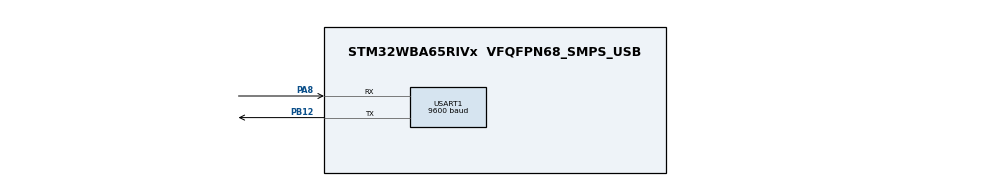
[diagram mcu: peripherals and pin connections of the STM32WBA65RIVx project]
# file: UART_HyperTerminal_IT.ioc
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CORTEX_M33_NS.userName=CORTEX_M33
Mcu.Family=STM32WBA
Mcu.Name=STM32WBA65RIVx
Mcu.Package=VFQFPN68_SMPS_USB
NVIC.PriorityGroup=NVIC_PRIORITYGROUP_4
NVIC.USART1_IRQn=true\:0\:0\:false\:false\:true\:true\:true\:true
OSC_IN.Mode=HSE-External-Oscillator
OSC_IN.Signal=RCC_OSC_IN
OSC_OUT.Mode=HSE-External-Oscillator
OSC_OUT.Signal=RCC_OSC_OUT
PA8.GPIO_PuPd=GPIO_PULLUP
PA8.Mode=Asynchronous
PA8.Signal=USART1_RX
PB12.GPIO_PuPd=GPIO_PULLUP
PB12.Mode=Asynchronous
PB12.Signal=USART1_TX
ProjectManager.HeapSize=0x200
ProjectManager.StackSize=0x400
ProjectManager.TargetToolchain=EWARM V9.20
RCC.ADCFreq_Value=100000000
RCC.AHB5CLKDivider=DIV4
RCC.AHBFreq_Value=100000000
RCC.APB1Freq_Value=100000000
RCC.APB1TimFreq_Value=100000000
RCC.APB2Freq_Value=100000000
RCC.APB2TimFreq_Value=100000000
RCC.CortexFreq_Value=12500000
RCC.HCLKFreq_Value=100000000
RCC.HSE_VALUE=32000000
RCC.HSI_VALUE=16000000
RCC.LSE_VALUE=32768
RCC.LSI1_VALUE=32000
RCC.LSI2_VALUE=32000
RCC.PLLFRACN=4096
RCC.PLLM=2
RCC.PLLN=12
RCC.PLLSourceVirtual=RCC_PLLSOURCE_HSE
RCC.SYSCLKFreq_VALUE=100000000
RCC.SYSCLKSourceVirtual=RCC_SYSCLKSOURCE_PLLCLK
RCC.VCOOutputFreq_Value=200000000
USART1.AutoBaudRateEnableParam=UART_ADVFEATURE_AUTOBAUDRATE_DISABLE
USART1.BaudRate=9600
USART1.DMADisableonRxErrorParam=ADVFEATURE_DMA_ENABLEONRXERROR
USART1.DataInvertParam=ADVFEATURE_DATAINV_DISABLE
USART1.MSBFirstParam=ADVFEATURE_MSBFIRST_DISABLE
USART1.Mode=MODE_TX_RX
USART1.OneBitSampling=UART_ONE_BIT_SAMPLE_DISABLE
USART1.OverSampling=UART_OVERSAMPLING_16
USART1.OverrunDisableParam=ADVFEATURE_OVERRUN_ENABLE
USART1.Parity=PARITY_ODD
USART1.RxPinLevelInvertParam=ADVFEATURE_RXINV_DISABLE
USART1.StopBits=STOPBITS_1
USART1.SwapParam=ADVFEATURE_SWAP_DISABLE
USART1.TxPinLevelInvertParam=ADVFEATURE_TXINV_DISABLE
USART1.VirtualMode-Asynchronous=VM_ASYNC
USART1.WordLength=WORDLENGTH_8B
VP_CORTEX_M33_NS_VS_Hclk.Mode=Hclk_Mode
VP_ICACHE_VS_ICACHE.Mode=DirectMappedCache
VP_PWR_VS_SECSignals.Mode=Security/Privilege
board=custom

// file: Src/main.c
/* USER CODE BEGIN Header */
/**
  ******************************************************************************
  * @file    UART/UART_HyperTerminal_IT/Src/main.c
  * @author  MCD Application Team
  * @brief   This sample code shows how to use UART HAL API to transmit
  *          and receive a data buffer with a communication process based on
  *          Interrupt transfer.
  *          The communication is done with the Hyperterminal PC application.
  ******************************************************************************
  * @attention
  *
  * Copyright (c) 2024 STMicroelectronics.
  * All rights reserved.
  *
  * This software is licensed under terms that can be found in the LICENSE file
  * in the root directory of this software component.
  * If no LICENSE file comes with this software, it is provided AS-IS.
  *
  ******************************************************************************
  */
/* USER CODE END Header */
#include "main.h"

UART_HandleTypeDef huart1;

/* USER CODE BEGIN PV */
/* Buffer used for transmission */
uint8_t aTxStartMessage[] = "\n\r ****UART-Hyperterminal communication based on IT ****\n\r Enter 10 characters using keyboard :\n\r";
uint8_t aTxEndMessage[] = "\n\r Example Finished\n\r";

/* Buffer used for reception */
uint8_t aRxBuffer[RXBUFFERSIZE];
/* USER CODE END PV */

void SystemClock_Config(void);
static void MX_GPIO_Init(void);
static void MX_USART1_UART_Init(void);
static void MX_ICACHE_Init(void);

int main(void)
{

  /* USER CODE BEGIN 1 */
  /* STM32WBAxx HAL library initialization:
       - Systick timer is configured by default as source of time base, but user
             can eventually implement his proper time base source (a general purpose
             timer for example or other time source), keeping in mind that Time base
             duration should be kept 1ms since PPP_TIMEOUT_VALUEs are defined and
             handled in milliseconds basis.
       - Set NVIC Group Priority to 4
       - Low Level Initialization
     */
  /* USER CODE END 1 */

  /* MCU Configuration--------------------------------------------------------*/

  /* Reset of all peripherals, Initializes the Flash interface and the Systick. */
  HAL_Init();

  /* Configure the system clock */
  SystemClock_Config();

  /* USER CODE BEGIN SysInit */
  /* Configure leds */
  /* Configure LD1 and LD3 */
  BSP_LED_Init(LD1);
  BSP_LED_Init(LD3);
  /* USER CODE END SysInit */

  /* Initialize all configured peripherals */
  MX_GPIO_Init();
  MX_USART1_UART_Init();
  MX_ICACHE_Init();
  /* USER CODE BEGIN 2 */

  /*##-1- Start the transmission process #####################################*/
  /* While the UART in reception process, user can transmit data through
     "aTxBuffer" buffer */
  if(HAL_UART_Transmit_IT(&huart1, (uint8_t*)aTxStartMessage, TXSTARTMESSAGESIZE)!= HAL_OK)
  {
    /* Transfer error in transmission process */
    Error_Handler();
  }

  /*##-2- Put UART peripheral in reception process ###########################*/
  /* Any data received will be stored in "aRxBuffer" buffer : the number max of
     data received is 10 */
  if(HAL_UART_Receive_IT(&huart1, (uint8_t *)aRxBuffer, RXBUFFERSIZE) != HAL_OK)
  {
    /* Transfer error in reception process */
    Error_Handler();
  }

  /*##-3- Wait for the end of the transfer ###################################*/
  /*  Before starting a new communication transfer, you need to check the current
      state of the peripheral; if it is busy you need to wait for the end of current
      transfer before starting a new one.
      For simplicity reasons, this example is just waiting till the end of the
      transfer, but application may perform other tasks while transfer operation
      is ongoing. */
  while (HAL_UART_GetState(&huart1) != HAL_UART_STATE_READY)
  {
  }

  /*##-4- Send the received Buffer ###########################################*/
  if(HAL_UART_Transmit_IT(&huart1, (uint8_t*)aRxBuffer, RXBUFFERSIZE)!= HAL_OK)
  {
    /* Transfer error in transmission process */
    Error_Handler();
  }

  /*##-5- Wait for the end of the transfer ###################################*/
  /*  Before starting a new communication transfer, you need to check the current
      state of the peripheral; if it is busy you need to wait for the end of current
      transfer before starting a new one.
      For simplicity reasons, this example is just waiting till the end of the
      transfer, but application may perform other tasks while transfer operation
      is ongoing. */
  while (HAL_UART_GetState(&huart1) != HAL_UART_STATE_READY)
  {
  }

  /*##-6- Send the End Message ###############################################*/
  if(HAL_UART_Transmit_IT(&huart1, (uint8_t*)aTxEndMessage, TXENDMESSAGESIZE)!= HAL_OK)
  {
    /* Transfer error in transmission process */
    Error_Handler();
  }

  /*##-7- Wait for the end of the transfer ###################################*/
  while (HAL_UART_GetState(&huart1) != HAL_UART_STATE_READY)
  {
  }

  /* Turn on LD1 if test passes then enter infinite loop */
  BSP_LED_On(LD1);

  /* USER CODE END 2 */

  /* Infinite loop */
  while (1)
  {

  }
}

void SystemClock_Config(void)
{
  RCC_OscInitTypeDef RCC_OscInitStruct = {0};
  RCC_ClkInitTypeDef RCC_ClkInitStruct = {0};

  /** Supply configuration update enable
  */
  HAL_PWREx_ConfigSupply(PWR_LDO_SUPPLY);

  /** Configure the main internal regulator output voltage
  */
  if (HAL_PWREx_ControlVoltageScaling(PWR_REGULATOR_VOLTAGE_SCALE1) != HAL_OK)
  {
    Error_Handler();
  }

  /** Initializes the CPU, AHB and APB busses clocks
  */
  RCC_OscInitStruct.OscillatorType = RCC_OSCILLATORTYPE_HSE;
  RCC_OscInitStruct.HSEState = RCC_HSE_ON;
  RCC_OscInitStruct.HSEDiv = RCC_HSE_DIV1;
  RCC_OscInitStruct.PLL1.PLLState = RCC_PLL_ON;
  RCC_OscInitStruct.PLL1.PLLSource = RCC_PLLSOURCE_HSE;
  RCC_OscInitStruct.PLL1.PLLM = 2;
  RCC_OscInitStruct.PLL1.PLLN = 12;
  RCC_OscInitStruct.PLL1.PLLP = 2;
  RCC_OscInitStruct.PLL1.PLLQ = 2;
  RCC_OscInitStruct.PLL1.PLLR = 2;
  RCC_OscInitStruct.PLL1.PLLFractional = 4096;
  if (HAL_RCC_OscConfig(&RCC_OscInitStruct) != HAL_OK)
  {
    Error_Handler();
  }

  /** Initializes the CPU, AHB and APB busses clocks
  */
  RCC_ClkInitStruct.ClockType = RCC_CLOCKTYPE_HCLK|RCC_CLOCKTYPE_SYSCLK
                              |RCC_CLOCKTYPE_PCLK1|RCC_CLOCKTYPE_PCLK2
                              |RCC_CLOCKTYPE_PCLK7|RCC_CLOCKTYPE_HCLK5;
  RCC_ClkInitStruct.SYSCLKSource = RCC_SYSCLKSOURCE_PLLCLK;
  RCC_ClkInitStruct.AHBCLKDivider = RCC_SYSCLK_DIV1;
  RCC_ClkInitStruct.APB1CLKDivider = RCC_HCLK_DIV1;
  RCC_ClkInitStruct.APB2CLKDivider = RCC_HCLK_DIV1;
  RCC_ClkInitStruct.APB7CLKDivider = RCC_HCLK_DIV1;
  RCC_ClkInitStruct.AHB5_PLL1_CLKDivider = RCC_SYSCLK_PLL1_DIV4;
  RCC_ClkInitStruct.AHB5_HSEHSI_CLKDivider = RCC_SYSCLK_HSEHSI_DIV1;

  if (HAL_RCC_ClockConfig(&RCC_ClkInitStruct, FLASH_LATENCY_3) != HAL_OK)
  {
    Error_Handler();
  }
}

static void MX_ICACHE_Init(void)
{

  /** Enable instruction cache in 1-way (direct mapped cache)
  */
  if (HAL_ICACHE_ConfigAssociativityMode(ICACHE_1WAY) != HAL_OK)
  {
    Error_Handler();
  }
  if (HAL_ICACHE_Enable() != HAL_OK)
  {
    Error_Handler();
  }

}

static void MX_USART1_UART_Init(void)
{

  huart1.Instance = USART1;
  huart1.Init.BaudRate = 9600;
  huart1.Init.WordLength = UART_WORDLENGTH_8B;
  huart1.Init.StopBits = UART_STOPBITS_1;
  huart1.Init.Parity = UART_PARITY_ODD;
  huart1.Init.Mode = UART_MODE_TX_RX;
  huart1.Init.HwFlowCtl = UART_HWCONTROL_NONE;
  huart1.Init.OverSampling = UART_OVERSAMPLING_16;
  huart1.Init.OneBitSampling = UART_ONE_BIT_SAMPLE_DISABLE;
  huart1.Init.ClockPrescaler = UART_PRESCALER_DIV1;
  huart1.AdvancedInit.AdvFeatureInit = UART_ADVFEATURE_NO_INIT;
  if (HAL_UART_Init(&huart1) != HAL_OK)
  {
    Error_Handler();
  }
  if (HAL_UARTEx_SetTxFifoThreshold(&huart1, UART_TXFIFO_THRESHOLD_1_8) != HAL_OK)
  {
    Error_Handler();
  }
  if (HAL_UARTEx_SetRxFifoThreshold(&huart1, UART_RXFIFO_THRESHOLD_1_8) != HAL_OK)
  {
    Error_Handler();
  }
  if (HAL_UARTEx_DisableFifoMode(&huart1) != HAL_OK)
  {
    Error_Handler();
  }

}

static void MX_GPIO_Init(void)
{

  /* GPIO Ports Clock Enable */
  __HAL_RCC_GPIOB_CLK_ENABLE();
  __HAL_RCC_GPIOA_CLK_ENABLE();

}

/* USER CODE BEGIN 4 */

/**
  * @brief  Tx Transfer completed callback
  * @param  UartHandle: UART handle.
  * @note   This example shows a simple way to report end of IT Tx transfer, and
  *         you can add your own implementation.
  * @retval None
  */
void HAL_UART_TxCpltCallback(UART_HandleTypeDef *UartHandle)
{
}

/**
  * @brief  Rx Transfer completed callback
  * @param  UartHandle: UART handle
  * @note   This example shows a simple way to report end of IT Rx transfer, and
  *         you can add your own implementation.
  * @retval None
  */
void HAL_UART_RxCpltCallback(UART_HandleTypeDef *UartHandle)
{
}

/**
  * @brief  UART error callbacks
  * @param  UartHandle: UART handle
  * @note   This example shows a simple way to report transfer error, and you can
  *         add your own implementation.
  * @retval None
  */
void HAL_UART_ErrorCallback(UART_HandleTypeDef *UartHandle)
{
  /* Turn LD3 on: Transfer error in reception/transmission process */
  BSP_LED_On(LD3);
}

/* USER CODE END 4 */

void Error_Handler(void)
{
  /* USER CODE BEGIN Error_Handler_Debug */
  /* User can add his own implementation to report the HAL error return state */
  /* Turn LD3 on */
  BSP_LED_On(LD3);
  while(1);
  /* USER CODE END Error_Handler_Debug */
}
